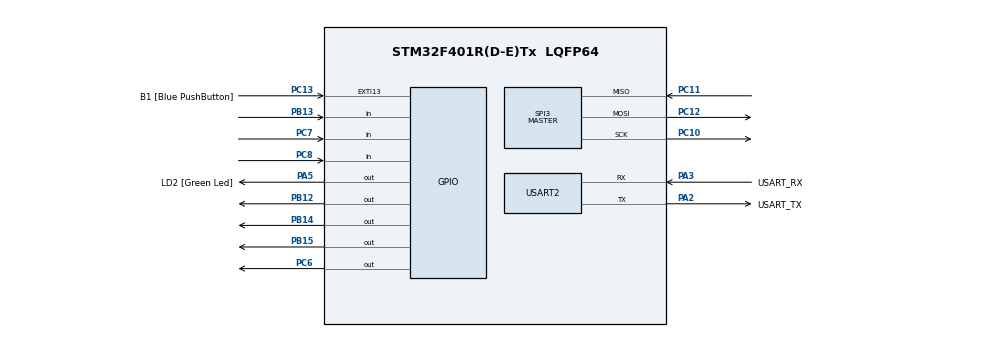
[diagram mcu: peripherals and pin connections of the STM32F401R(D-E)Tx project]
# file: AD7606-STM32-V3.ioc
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Mcu.Family=STM32F4
Mcu.Name=STM32F401R(D-E)Tx
Mcu.Package=LQFP64
NVIC.EXTI15_10_IRQn=true\:0\:0\:false\:false\:true\:true\:true\:true
NVIC.PriorityGroup=NVIC_PRIORITYGROUP_0
NVIC.SPI3_IRQn=true\:0\:0\:false\:false\:true\:true\:true\:true
NVIC.TIM1_UP_TIM10_IRQn=true\:0\:0\:false\:false\:true\:true\:true\:true
NVIC.USART2_IRQn=true\:0\:0\:false\:false\:true\:true\:true\:true
PA13.GPIO_Label=TMS
PA13.Mode=Serial_Wire
PA13.Signal=SYS_JTMS-SWDIO
PA14.GPIO_Label=TCK
PA14.Mode=Serial_Wire
PA14.Signal=SYS_JTCK-SWCLK
PA2.GPIO_Label=USART_TX
PA2.GPIO_Mode=GPIO_MODE_AF_PP
PA2.GPIO_PuPd=GPIO_NOPULL
PA2.GPIO_Speed=GPIO_SPEED_FREQ_LOW
PA2.Mode=Asynchronous
PA2.Signal=USART2_TX
PA3.GPIO_Label=USART_RX
PA3.GPIO_Mode=GPIO_MODE_AF_PP
PA3.GPIO_PuPd=GPIO_NOPULL
PA3.GPIO_Speed=GPIO_SPEED_FREQ_LOW
PA3.Mode=Asynchronous
PA3.Signal=USART2_RX
PA5.GPIO_Label=LD2 [Green Led]
PA5.GPIO_Mode=GPIO_MODE_OUTPUT_PP
PA5.GPIO_PuPd=GPIO_NOPULL
PA5.GPIO_Speed=GPIO_SPEED_FREQ_LOW
PA5.Signal=GPIO_Output
PB12.Signal=GPIO_Output
PB13.Signal=GPIO_Input
PB14.Signal=GPIO_Output
PB15.Signal=GPIO_Output
PB3.GPIO_Label=SWO
PB3.Signal=SYS_JTDO-SWO
PC10.Mode=Full_Duplex_Master
PC10.Signal=SPI3_SCK
PC11.Mode=Full_Duplex_Master
PC11.Signal=SPI3_MISO
PC12.Mode=Full_Duplex_Master
PC12.Signal=SPI3_MOSI
PC13-ANTI_TAMP.GPIO_Label=B1 [Blue PushButton]
PC13-ANTI_TAMP.GPIO_ModeDefaultEXTI=GPIO_MODE_IT_FALLING
PC13-ANTI_TAMP.GPIO_PuPd=GPIO_NOPULL
PC13-ANTI_TAMP.Signal=GPXTI13
PC14-OSC32_IN.Mode=LSE-External-Oscillator
PC14-OSC32_IN.Signal=RCC_OSC32_IN
PC15-OSC32_OUT.Mode=LSE-External-Oscillator
PC15-OSC32_OUT.Signal=RCC_OSC32_OUT
PC6.Signal=GPIO_Output
PC7.Signal=GPIO_Input
PC8.Signal=GPIO_Input
PH0\ -\ OSC_IN.Mode=HSE-External-Clock-Source
PH0\ -\ OSC_IN.Signal=RCC_OSC_IN
PH1\ -\ OSC_OUT.Mode=HSE-External-Clock-Source
PH1\ -\ OSC_OUT.Signal=RCC_OSC_OUT
ProjectManager.HeapSize=0x200
ProjectManager.StackSize=0x400
ProjectManager.TargetToolchain=STM32CubeIDE
RCC.48MHZClocksFreq_Value=48000000
RCC.AHBFreq_Value=84000000
RCC.APB1CLKDivider=RCC_HCLK_DIV2
RCC.APB1Freq_Value=42000000
RCC.APB1TimFreq_Value=84000000
RCC.APB2Freq_Value=84000000
RCC.APB2TimFreq_Value=84000000
RCC.CortexFreq_Value=84000000
RCC.HCLKFreq_Value=84000000
RCC.HSE_VALUE=8000000
RCC.HSI_VALUE=16000000
RCC.PLLN=336
RCC.PLLP=RCC_PLLP_DIV4
RCC.PLLQ=7
RCC.SYSCLKFreq_VALUE=84000000
RCC.SYSCLKSource=RCC_SYSCLKSOURCE_PLLCLK
RCC.VCOOutputFreq_Value=336000000
SPI3.DataSize=SPI_DATASIZE_16BIT
SPI3.Direction=SPI_DIRECTION_2LINES
SPI3.Mode=SPI_MODE_MASTER
SPI3.VirtualType=VM_MASTER
USART2.VirtualMode=VM_ASYNC
VP_TIM10_VS_ClockSourceINT.Mode=Enable_Timer
board=NUCLEO-F401RE

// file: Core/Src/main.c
/* USER CODE BEGIN Header */
/**
  ******************************************************************************
  * @file           : main.c
  * @brief          : Main program body
  ******************************************************************************
  * @attention
  *
  * Copyright (c) 2024 STMicroelectronics.
  * All rights reserved.
  *
  * This software is licensed under terms that can be found in the LICENSE file
  * in the root directory of this software component.
  * If no LICENSE file comes with this software, it is provided AS-IS.
  *
  ******************************************************************************
  */
/* USER CODE END Header */
#include "main.h"

/* USER CODE BEGIN Includes */
#include <stdio.h>
#include <string.h>
#include <stdlib.h>

/* USER CODE END Includes */

/* USER CODE BEGIN PTD */

  // SET PIN CONFIGURATIONS
  /* AD7606   ->    STM32
   * BUSY 		 -> PC7
   * RESET 		 -> PC6
   * CONVST 	 -> PB15
   * CHIP_SELECT -> PB14 (SPI CS)
   * D7_OUT 	 -> PC11  (MISO)  PB13
   * D8_OUT      -> PC8
   * RD 		 -> PB12    //PC10 (SPI SCLK)  (prima era pb12)
   * */
#define BUSY_PORT GPIOC
#define BUSY_PIN GPIO_PIN_7
#define RESET_PORT GPIOC
#define RESET_PIN GPIO_PIN_6
#define CONVST_PORT GPIOB
#define CONVST_PIN GPIO_PIN_15
#define CS_PORT GPIOB
#define CS_PIN GPIO_PIN_14
#define D7_PORT GPIOC
#define D7_PIN GPIO_PIN_11
#define RD_PORT GPIOB
#define RD_PIN GPIO_PIN_12
#define D8_PORT GPIOC
#define D8_PIN GPIO_PIN_8

#define MAXBUFFERSIZE 100

/* USER CODE END PTD */

SPI_HandleTypeDef hspi3;

TIM_HandleTypeDef htim10;

UART_HandleTypeDef huart2;

void SystemClock_Config(void);
static void MX_GPIO_Init(void);
static void MX_USART2_UART_Init(void);
static void MX_SPI3_Init(void);
static void MX_TIM10_Init(void);

/* USER CODE BEGIN 0 */
#define TOTAL_RAW_BYTES 128   //16 byte = 128 bit
uint16_t parsed[8];  //was 8
uint16_t raw[TOTAL_RAW_BYTES];

uint8_t RxBuf[MAXBUFFERSIZE];
uint8_t TxBuf[MAXBUFFERSIZE];
int char_counter = 0;
uint8_t WTxBuf [MAXBUFFERSIZE] = "Hello from STM32 \r\n";  // Message to be transmitted over UART

uint8_t commd_on [MAXBUFFERSIZE] = "ON";
uint8_t commd_off [MAXBUFFERSIZE] = "OFF";

void parseRawBytes();

void read(int16_t *rawdatabuffer);
int twos_complement(int num, int bits);

/* USER CODE END 0 */

int main(void)
{

  /* MCU Configuration--------------------------------------------------------*/

  /* Reset of all peripherals, Initializes the Flash interface and the Systick. */
  HAL_Init();

  /* USER CODE BEGIN Init */
  // SET CS LOW
  HAL_GPIO_WritePin(CS_PORT, CS_PIN, 0);
  // SET CONVST HIGH
  HAL_GPIO_WritePin(CONVST_PORT, CONVST_PIN, 1);  // convst high
  //RESET LOW
  HAL_GPIO_WritePin(RESET_PORT, RESET_PIN, 0);
  // RESET HIGH
  HAL_GPIO_WritePin(RESET_PORT, RESET_PIN, 1);
  //RESET LOW
  HAL_GPIO_WritePin(RESET_PORT, RESET_PIN, 0);
  /* USER CODE END Init */

  /* Configure the system clock */
  SystemClock_Config();

  /* Initialize all configured peripherals */
  MX_GPIO_Init();
  MX_USART2_UART_Init();
  MX_SPI3_Init();
  MX_TIM10_Init();
  /* USER CODE BEGIN 2 */
  //HAL_UART_Receive_IT(&huart2, RxBuf, MAXBUFFERSIZE);
  HAL_UART_RxCpltCallback(&huart2);

  int bytesToRead = TOTAL_RAW_BYTES;

  /* USER CODE END 2 */

  /* Infinite loop */
  /* USER CODE BEGIN WHILE */
  while (1)
  {

	  uint16_t data[8];
	  float convertedData[8];
	  // READ DATA
	  read(data);

	  for(int i=0; i<8; i++){
		  int complementTwo = twos_complement(data[i], 16);
		  convertedData[i] = complementTwo*(5*2.5)/(32768*2);
	  }
	  for(int i=0; i<8; i++) {
		  char message_channel[60];
		  snprintf(message_channel, sizeof(message_channel), "%d,%f\n", i+1, convertedData[i]);
		  HAL_UART_Transmit(&huart2, (uint8_t *)message_channel, strlen(message_channel), HAL_MAX_DELAY);
	  }
	  HAL_Delay(3000);
    /* USER CODE END WHILE */

  }
}

void SystemClock_Config(void)
{
  RCC_OscInitTypeDef RCC_OscInitStruct = {0};
  RCC_ClkInitTypeDef RCC_ClkInitStruct = {0};

  /** Configure the main internal regulator output voltage
  */
  __HAL_RCC_PWR_CLK_ENABLE();
  __HAL_PWR_VOLTAGESCALING_CONFIG(PWR_REGULATOR_VOLTAGE_SCALE2);

  /** Initializes the RCC Oscillators according to the specified parameters
  * in the RCC_OscInitTypeDef structure.
  */
  RCC_OscInitStruct.OscillatorType = RCC_OSCILLATORTYPE_HSI;
  RCC_OscInitStruct.HSIState = RCC_HSI_ON;
  RCC_OscInitStruct.HSICalibrationValue = RCC_HSICALIBRATION_DEFAULT;
  RCC_OscInitStruct.PLL.PLLState = RCC_PLL_ON;
  RCC_OscInitStruct.PLL.PLLSource = RCC_PLLSOURCE_HSI;
  RCC_OscInitStruct.PLL.PLLM = 8;
  RCC_OscInitStruct.PLL.PLLN = 80;
  RCC_OscInitStruct.PLL.PLLP = RCC_PLLP_DIV2;
  RCC_OscInitStruct.PLL.PLLQ = 7;
  if (HAL_RCC_OscConfig(&RCC_OscInitStruct) != HAL_OK)
  {
    Error_Handler();
  }

  /** Initializes the CPU, AHB and APB buses clocks
  */
  RCC_ClkInitStruct.ClockType = RCC_CLOCKTYPE_HCLK|RCC_CLOCKTYPE_SYSCLK
                              |RCC_CLOCKTYPE_PCLK1|RCC_CLOCKTYPE_PCLK2;
  RCC_ClkInitStruct.SYSCLKSource = RCC_SYSCLKSOURCE_PLLCLK;
  RCC_ClkInitStruct.AHBCLKDivider = RCC_SYSCLK_DIV1;
  RCC_ClkInitStruct.APB1CLKDivider = RCC_HCLK_DIV2;
  RCC_ClkInitStruct.APB2CLKDivider = RCC_HCLK_DIV2;

  if (HAL_RCC_ClockConfig(&RCC_ClkInitStruct, FLASH_LATENCY_2) != HAL_OK)
  {
    Error_Handler();
  }
}

static void MX_SPI3_Init(void)
{

  /* SPI3 parameter configuration*/
  hspi3.Instance = SPI3;
  hspi3.Init.Mode = SPI_MODE_MASTER;
  hspi3.Init.Direction = SPI_DIRECTION_2LINES_RXONLY;
  hspi3.Init.DataSize = SPI_DATASIZE_16BIT;
  hspi3.Init.CLKPolarity = SPI_POLARITY_LOW;
  hspi3.Init.CLKPhase = SPI_PHASE_1EDGE;
  hspi3.Init.NSS = SPI_NSS_SOFT;
  hspi3.Init.BaudRatePrescaler = SPI_BAUDRATEPRESCALER_2;
  hspi3.Init.FirstBit = SPI_FIRSTBIT_MSB;
  hspi3.Init.TIMode = SPI_TIMODE_DISABLE;
  hspi3.Init.CRCCalculation = SPI_CRCCALCULATION_DISABLE;
  hspi3.Init.CRCPolynomial = 10;
  if (HAL_SPI_Init(&hspi3) != HAL_OK)
  {
    Error_Handler();
  }

}

static void MX_TIM10_Init(void)
{

  htim10.Instance = TIM10;
  htim10.Init.Prescaler = 0;
  htim10.Init.CounterMode = TIM_COUNTERMODE_UP;
  htim10.Init.Period = 65535;
  htim10.Init.ClockDivision = TIM_CLOCKDIVISION_DIV1;
  htim10.Init.AutoReloadPreload = TIM_AUTORELOAD_PRELOAD_DISABLE;
  if (HAL_TIM_Base_Init(&htim10) != HAL_OK)
  {
    Error_Handler();
  }

}

static void MX_USART2_UART_Init(void)
{

  huart2.Instance = USART2;
  huart2.Init.BaudRate = 115200;
  huart2.Init.WordLength = UART_WORDLENGTH_8B;
  huart2.Init.StopBits = UART_STOPBITS_1;
  huart2.Init.Parity = UART_PARITY_NONE;
  huart2.Init.Mode = UART_MODE_TX_RX;
  huart2.Init.HwFlowCtl = UART_HWCONTROL_NONE;
  huart2.Init.OverSampling = UART_OVERSAMPLING_8;
  if (HAL_UART_Init(&huart2) != HAL_OK)
  {
    Error_Handler();
  }

}

static void MX_GPIO_Init(void)
{
  GPIO_InitTypeDef GPIO_InitStruct = {0};

  /* GPIO Ports Clock Enable */
  __HAL_RCC_GPIOC_CLK_ENABLE();
  __HAL_RCC_GPIOH_CLK_ENABLE();
  __HAL_RCC_GPIOA_CLK_ENABLE();
  __HAL_RCC_GPIOB_CLK_ENABLE();

  /*Configure GPIO pin Output Level */
  HAL_GPIO_WritePin(LD2_GPIO_Port, LD2_Pin, GPIO_PIN_RESET);

  /*Configure GPIO pin Output Level */
  HAL_GPIO_WritePin(GPIOB, GPIO_PIN_12|GPIO_PIN_14|GPIO_PIN_15, GPIO_PIN_RESET);

  /*Configure GPIO pin Output Level */
  HAL_GPIO_WritePin(GPIOC, GPIO_PIN_6, GPIO_PIN_RESET);

  /*Configure GPIO pin : B1_Pin */
  GPIO_InitStruct.Pin = B1_Pin;
  GPIO_InitStruct.Mode = GPIO_MODE_IT_FALLING;
  GPIO_InitStruct.Pull = GPIO_NOPULL;
  HAL_GPIO_Init(B1_GPIO_Port, &GPIO_InitStruct);

  /*Configure GPIO pin : LD2_Pin */
  GPIO_InitStruct.Pin = LD2_Pin;
  GPIO_InitStruct.Mode = GPIO_MODE_OUTPUT_PP;
  GPIO_InitStruct.Pull = GPIO_NOPULL;
  GPIO_InitStruct.Speed = GPIO_SPEED_FREQ_LOW;
  HAL_GPIO_Init(LD2_GPIO_Port, &GPIO_InitStruct);

  /*Configure GPIO pins : PB12 PB14 PB15 */
  GPIO_InitStruct.Pin = GPIO_PIN_12|GPIO_PIN_14|GPIO_PIN_15;
  GPIO_InitStruct.Mode = GPIO_MODE_OUTPUT_PP;
  GPIO_InitStruct.Pull = GPIO_NOPULL;
  GPIO_InitStruct.Speed = GPIO_SPEED_FREQ_LOW;
  HAL_GPIO_Init(GPIOB, &GPIO_InitStruct);

  /*Configure GPIO pin : PB13 */
  GPIO_InitStruct.Pin = GPIO_PIN_13;
  GPIO_InitStruct.Mode = GPIO_MODE_INPUT;
  GPIO_InitStruct.Pull = GPIO_NOPULL;
  HAL_GPIO_Init(GPIOB, &GPIO_InitStruct);

  /*Configure GPIO pin : PC6 */
  GPIO_InitStruct.Pin = GPIO_PIN_6;
  GPIO_InitStruct.Mode = GPIO_MODE_OUTPUT_PP;
  GPIO_InitStruct.Pull = GPIO_NOPULL;
  GPIO_InitStruct.Speed = GPIO_SPEED_FREQ_LOW;
  HAL_GPIO_Init(GPIOC, &GPIO_InitStruct);

  /*Configure GPIO pins : PC7 PC8 */
  GPIO_InitStruct.Pin = GPIO_PIN_7|GPIO_PIN_8;
  GPIO_InitStruct.Mode = GPIO_MODE_INPUT;
  GPIO_InitStruct.Pull = GPIO_NOPULL;
  HAL_GPIO_Init(GPIOC, &GPIO_InitStruct);

  /* EXTI interrupt init*/
  HAL_NVIC_SetPriority(EXTI15_10_IRQn, 0, 0);
  HAL_NVIC_EnableIRQ(EXTI15_10_IRQn);

}

/* USER CODE BEGIN 4 */

//callback for usart when receive data
void HAL_GPIO_EXTI_Callback(uint16_t GPIO_Pin)
{
	HAL_UART_Transmit(&huart2, WTxBuf, sizeof(WTxBuf),100);
	HAL_UART_Receive_IT(&huart2, RxBuf, 1);
}

void cmd_check()
{
	char *ptr = strtok(TxBuf, ",");
	// cast to char needed because strcmp accepts signed values, not unsigned
	if (strcmp((char *)ptr, (char *) commd_on) == 0) // equal to zero if match
	{
		// fai cose
		//HAL_GPIO_WritePin (GPIOA, GPIO_PIN_5,GPIO_PIN_SET);
		// if fai cose has success :
		HAL_UART_Transmit(&huart2, (uint8_t *)TxBuf , sizeof(TxBuf),10);  //ritorna il messaggio iniziale
	}
	else if (strcmp((char *)TxBuf, (char *) commd_off) == 0)
	{
		//non serve perchè riceverà solo ON
		//HAL_UART_Transmit(&huart2, (uint8_t *)TxBuf, sizeof(TxBuf),10);
		//HAL_GPIO_WritePin (GPIOA, GPIO_PIN_5,GPIO_PIN_RESET);
	}
	else
	{
		HAL_UART_Transmit(&huart2, (uint8_t *)"WRONG CMD\r\n", sizeof("WRONG CMD\r\n"),10);
	}
}

//receive and store data coming from uart. We receive: topic, payload
void HAL_UART_RxCpltCallback(UART_HandleTypeDef *huart)
{
	if (RxBuf[0] == 13){	// Check if character is enter
		HAL_UART_Transmit(&huart2, (uint8_t *)"\r\n", sizeof("\r\n"),10);
		cmd_check();
		memset(TxBuf, '\0', sizeof(TxBuf));  //strcpy(TxBuf, ""); //TxBuf[0] = '\0'; //flush buffer
		char_counter = 0; //set char_counter to zero
	}
	else if(RxBuf[0] == 8){  // Check if character is backspace
		HAL_UART_Transmit(&huart2, (uint8_t *)"\b \b", sizeof("\b \b"),10);
		TxBuf[--char_counter] = NULL; //remove from our buffer previous letter
	}else{	//Otherwise store new character inside our buffer
		TxBuf[char_counter++] = RxBuf[0];
		HAL_UART_Transmit(&huart2, RxBuf, sizeof(RxBuf),10); //Echo single character
	}
	HAL_UART_Receive_IT(&huart2 , RxBuf, 1); // Restart UART in Interrupt mode
}

void parseRawBytes() {
  for(int i = 0; i<(sizeof(parsed) / sizeof(int));i++)
    {
      parsed[i] = (raw[i*2] << 8) + raw[(i*2)+1];
    }
}

void read(int16_t *rawdatabuffer){
	uint16_t value1 = 0;
	uint16_t value2 = 0;

	//pulse convst to start conversion
	HAL_GPIO_WritePin(CONVST_PORT, CONVST_PIN, 0);
	HAL_GPIO_WritePin(CONVST_PORT, CONVST_PIN, 1);

	//set CS low to enable DOUT lines to shift out data
	HAL_GPIO_WritePin(CS_PORT, CS_PIN, 0);

	// Wait until busy goes to 0
	while(HAL_GPIO_ReadPin(BUSY_PORT, BUSY_PIN) == 1){
		//wait
	}

	// read data
	for(int k=0; k<4; k++){
		for(int i=15; i>=0; i--){
			//pulse RD to get data -> should already be pulsed by sclk pin
			HAL_GPIO_WritePin(RD_PORT, RD_PIN, 1);
			HAL_GPIO_WritePin(RD_PORT, RD_PIN, 0);

			value1 += HAL_GPIO_ReadPin(D7_PORT, D7_PIN) << i;
			value2 += HAL_GPIO_ReadPin(D8_PORT, D8_PIN) << i;
		}
		*(rawdatabuffer + k) = value1;
		*(rawdatabuffer + 4 + k) = value2;
	}
	//set cs high again
	HAL_GPIO_WritePin(CS_PORT, CS_PIN, 1);
}

int twos_complement(int num, int bits) {
    // Calculate the mask for the given number of bits
    int mask = (1 << (bits - 1)) - 1;  // Create a mask of all 1s for given number of bits

    // Check if num is negative
    if (num & (1 << (bits - 1))) {
        // Negative number: apply two's complement
        return (num & mask) - (1 << (bits - 1));
    } else {
        // Positive number or zero: two's complement is the number itself
        return num;
    }
}

/* USER CODE END 4 */

void Error_Handler(void)
{
  __disable_irq();
  while (1)
  {
  }
}
